# Generated by FakeRAM 2.0
VERSION 5.7 ;
BUSBITCHARS "[]" ;
PROPERTYDEFINITIONS
  MACRO width INTEGER ;
  MACRO depth INTEGER ;
  MACRO banks INTEGER ;
END PROPERTYDEFINITIONS
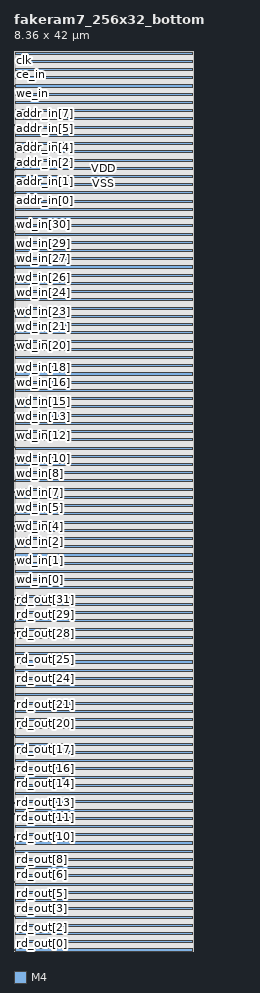
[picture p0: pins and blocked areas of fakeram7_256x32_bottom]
MACRO fakeram7_256x32_bottom
  PROPERTY width 32 ;
  PROPERTY depth 256 ;
  PROPERTY banks 2 ;
  FOREIGN fakeram7_256x32_bottom 0 0 ;
  SYMMETRY X Y R90 ;
  SIZE 8.360 BY 42.000 ;
  CLASS BLOCK ;
  PIN rd_out[0]
    DIRECTION OUTPUT ;
    USE SIGNAL ;
    SHAPE ABUTMENT ;
    PORT
      LAYER M4 ;
      RECT 0.000 0.039 0.024 0.063 ;
    END
  END rd_out[0]
  PIN rd_out[1]
    DIRECTION OUTPUT ;
    USE SIGNAL ;
    SHAPE ABUTMENT ;
    PORT
      LAYER M4 ;
      RECT 0.000 0.567 0.024 0.591 ;
    END
  END rd_out[1]
  PIN rd_out[2]
    DIRECTION OUTPUT ;
    USE SIGNAL ;
    SHAPE ABUTMENT ;
    PORT
      LAYER M4 ;
      RECT 0.000 1.095 0.024 1.119 ;
    END
  END rd_out[2]
  PIN rd_out[3]
    DIRECTION OUTPUT ;
    USE SIGNAL ;
    SHAPE ABUTMENT ;
    PORT
      LAYER M4 ;
      RECT 0.000 1.623 0.024 1.647 ;
    END
  END rd_out[3]
  PIN rd_out[4]
    DIRECTION OUTPUT ;
    USE SIGNAL ;
    SHAPE ABUTMENT ;
    PORT
      LAYER M4 ;
      RECT 0.000 2.151 0.024 2.175 ;
    END
  END rd_out[4]
  PIN rd_out[5]
    DIRECTION OUTPUT ;
    USE SIGNAL ;
    SHAPE ABUTMENT ;
    PORT
      LAYER M4 ;
      RECT 0.000 2.679 0.024 2.703 ;
    END
  END rd_out[5]
  PIN rd_out[6]
    DIRECTION OUTPUT ;
    USE SIGNAL ;
    SHAPE ABUTMENT ;
    PORT
      LAYER M4 ;
      RECT 0.000 3.207 0.024 3.231 ;
    END
  END rd_out[6]
  PIN rd_out[7]
    DIRECTION OUTPUT ;
    USE SIGNAL ;
    SHAPE ABUTMENT ;
    PORT
      LAYER M4 ;
      RECT 0.000 3.735 0.024 3.759 ;
    END
  END rd_out[7]
  PIN rd_out[8]
    DIRECTION OUTPUT ;
    USE SIGNAL ;
    SHAPE ABUTMENT ;
    PORT
      LAYER M4 ;
      RECT 0.000 4.263 0.024 4.287 ;
    END
  END rd_out[8]
  PIN rd_out[9]
    DIRECTION OUTPUT ;
    USE SIGNAL ;
    SHAPE ABUTMENT ;
    PORT
      LAYER M4 ;
      RECT 0.000 4.791 0.024 4.815 ;
    END
  END rd_out[9]
  PIN rd_out[10]
    DIRECTION OUTPUT ;
    USE SIGNAL ;
    SHAPE ABUTMENT ;
    PORT
      LAYER M4 ;
      RECT 0.000 5.319 0.024 5.343 ;
    END
  END rd_out[10]
  PIN rd_out[11]
    DIRECTION OUTPUT ;
    USE SIGNAL ;
    SHAPE ABUTMENT ;
    PORT
      LAYER M4 ;
      RECT 0.000 5.847 0.024 5.871 ;
    END
  END rd_out[11]
  PIN rd_out[12]
    DIRECTION OUTPUT ;
    USE SIGNAL ;
    SHAPE ABUTMENT ;
    PORT
      LAYER M4 ;
      RECT 0.000 6.375 0.024 6.399 ;
    END
  END rd_out[12]
  PIN rd_out[13]
    DIRECTION OUTPUT ;
    USE SIGNAL ;
    SHAPE ABUTMENT ;
    PORT
      LAYER M4 ;
      RECT 0.000 6.903 0.024 6.927 ;
    END
  END rd_out[13]
  PIN rd_out[14]
    DIRECTION OUTPUT ;
    USE SIGNAL ;
    SHAPE ABUTMENT ;
    PORT
      LAYER M4 ;
      RECT 0.000 7.431 0.024 7.455 ;
    END
  END rd_out[14]
  PIN rd_out[15]
    DIRECTION OUTPUT ;
    USE SIGNAL ;
    SHAPE ABUTMENT ;
    PORT
      LAYER M4 ;
      RECT 0.000 7.959 0.024 7.983 ;
    END
  END rd_out[15]
  PIN rd_out[16]
    DIRECTION OUTPUT ;
    USE SIGNAL ;
    SHAPE ABUTMENT ;
    PORT
      LAYER M4 ;
      RECT 0.000 8.487 0.024 8.511 ;
    END
  END rd_out[16]
  PIN rd_out[17]
    DIRECTION OUTPUT ;
    USE SIGNAL ;
    SHAPE ABUTMENT ;
    PORT
      LAYER M4 ;
      RECT 0.000 9.015 0.024 9.039 ;
    END
  END rd_out[17]
  PIN rd_out[18]
    DIRECTION OUTPUT ;
    USE SIGNAL ;
    SHAPE ABUTMENT ;
    PORT
      LAYER M4 ;
      RECT 0.000 9.543 0.024 9.567 ;
    END
  END rd_out[18]
  PIN rd_out[19]
    DIRECTION OUTPUT ;
    USE SIGNAL ;
    SHAPE ABUTMENT ;
    PORT
      LAYER M4 ;
      RECT 0.000 10.071 0.024 10.095 ;
    END
  END rd_out[19]
  PIN rd_out[20]
    DIRECTION OUTPUT ;
    USE SIGNAL ;
    SHAPE ABUTMENT ;
    PORT
      LAYER M4 ;
      RECT 0.000 10.599 0.024 10.623 ;
    END
  END rd_out[20]
  PIN rd_out[21]
    DIRECTION OUTPUT ;
    USE SIGNAL ;
    SHAPE ABUTMENT ;
    PORT
      LAYER M4 ;
      RECT 0.000 11.127 0.024 11.151 ;
    END
  END rd_out[21]
  PIN rd_out[22]
    DIRECTION OUTPUT ;
    USE SIGNAL ;
    SHAPE ABUTMENT ;
    PORT
      LAYER M4 ;
      RECT 0.000 11.655 0.024 11.679 ;
    END
  END rd_out[22]
  PIN rd_out[23]
    DIRECTION OUTPUT ;
    USE SIGNAL ;
    SHAPE ABUTMENT ;
    PORT
      LAYER M4 ;
      RECT 0.000 12.183 0.024 12.207 ;
    END
  END rd_out[23]
  PIN rd_out[24]
    DIRECTION OUTPUT ;
    USE SIGNAL ;
    SHAPE ABUTMENT ;
    PORT
      LAYER M4 ;
      RECT 0.000 12.711 0.024 12.735 ;
    END
  END rd_out[24]
  PIN rd_out[25]
    DIRECTION OUTPUT ;
    USE SIGNAL ;
    SHAPE ABUTMENT ;
    PORT
      LAYER M4 ;
      RECT 0.000 13.239 0.024 13.263 ;
    END
  END rd_out[25]
  PIN rd_out[26]
    DIRECTION OUTPUT ;
    USE SIGNAL ;
    SHAPE ABUTMENT ;
    PORT
      LAYER M4 ;
      RECT 0.000 13.767 0.024 13.791 ;
    END
  END rd_out[26]
  PIN rd_out[27]
    DIRECTION OUTPUT ;
    USE SIGNAL ;
    SHAPE ABUTMENT ;
    PORT
      LAYER M4 ;
      RECT 0.000 14.295 0.024 14.319 ;
    END
  END rd_out[27]
  PIN rd_out[28]
    DIRECTION OUTPUT ;
    USE SIGNAL ;
    SHAPE ABUTMENT ;
    PORT
      LAYER M4 ;
      RECT 0.000 14.823 0.024 14.847 ;
    END
  END rd_out[28]
  PIN rd_out[29]
    DIRECTION OUTPUT ;
    USE SIGNAL ;
    SHAPE ABUTMENT ;
    PORT
      LAYER M4 ;
      RECT 0.000 15.351 0.024 15.375 ;
    END
  END rd_out[29]
  PIN rd_out[30]
    DIRECTION OUTPUT ;
    USE SIGNAL ;
    SHAPE ABUTMENT ;
    PORT
      LAYER M4 ;
      RECT 0.000 15.879 0.024 15.903 ;
    END
  END rd_out[30]
  PIN rd_out[31]
    DIRECTION OUTPUT ;
    USE SIGNAL ;
    SHAPE ABUTMENT ;
    PORT
      LAYER M4 ;
      RECT 0.000 16.407 0.024 16.431 ;
    END
  END rd_out[31]
  PIN wd_in[0]
    DIRECTION INPUT ;
    USE SIGNAL ;
    SHAPE ABUTMENT ;
    PORT
      LAYER M4 ;
      RECT 0.000 17.703 0.024 17.727 ;
    END
  END wd_in[0]
  PIN wd_in[1]
    DIRECTION INPUT ;
    USE SIGNAL ;
    SHAPE ABUTMENT ;
    PORT
      LAYER M4 ;
      RECT 0.000 18.231 0.024 18.255 ;
    END
  END wd_in[1]
  PIN wd_in[2]
    DIRECTION INPUT ;
    USE SIGNAL ;
    SHAPE ABUTMENT ;
    PORT
      LAYER M4 ;
      RECT 0.000 18.759 0.024 18.783 ;
    END
  END wd_in[2]
  PIN wd_in[3]
    DIRECTION INPUT ;
    USE SIGNAL ;
    SHAPE ABUTMENT ;
    PORT
      LAYER M4 ;
      RECT 0.000 19.287 0.024 19.311 ;
    END
  END wd_in[3]
  PIN wd_in[4]
    DIRECTION INPUT ;
    USE SIGNAL ;
    SHAPE ABUTMENT ;
    PORT
      LAYER M4 ;
      RECT 0.000 19.815 0.024 19.839 ;
    END
  END wd_in[4]
  PIN wd_in[5]
    DIRECTION INPUT ;
    USE SIGNAL ;
    SHAPE ABUTMENT ;
    PORT
      LAYER M4 ;
      RECT 0.000 20.343 0.024 20.367 ;
    END
  END wd_in[5]
  PIN wd_in[6]
    DIRECTION INPUT ;
    USE SIGNAL ;
    SHAPE ABUTMENT ;
    PORT
      LAYER M4 ;
      RECT 0.000 20.871 0.024 20.895 ;
    END
  END wd_in[6]
  PIN wd_in[7]
    DIRECTION INPUT ;
    USE SIGNAL ;
    SHAPE ABUTMENT ;
    PORT
      LAYER M4 ;
      RECT 0.000 21.399 0.024 21.423 ;
    END
  END wd_in[7]
  PIN wd_in[8]
    DIRECTION INPUT ;
    USE SIGNAL ;
    SHAPE ABUTMENT ;
    PORT
      LAYER M4 ;
      RECT 0.000 21.927 0.024 21.951 ;
    END
  END wd_in[8]
  PIN wd_in[9]
    DIRECTION INPUT ;
    USE SIGNAL ;
    SHAPE ABUTMENT ;
    PORT
      LAYER M4 ;
      RECT 0.000 22.455 0.024 22.479 ;
    END
  END wd_in[9]
  PIN wd_in[10]
    DIRECTION INPUT ;
    USE SIGNAL ;
    SHAPE ABUTMENT ;
    PORT
      LAYER M4 ;
      RECT 0.000 22.983 0.024 23.007 ;
    END
  END wd_in[10]
  PIN wd_in[11]
    DIRECTION INPUT ;
    USE SIGNAL ;
    SHAPE ABUTMENT ;
    PORT
      LAYER M4 ;
      RECT 0.000 23.511 0.024 23.535 ;
    END
  END wd_in[11]
  PIN wd_in[12]
    DIRECTION INPUT ;
    USE SIGNAL ;
    SHAPE ABUTMENT ;
    PORT
      LAYER M4 ;
      RECT 0.000 24.039 0.024 24.063 ;
    END
  END wd_in[12]
  PIN wd_in[13]
    DIRECTION INPUT ;
    USE SIGNAL ;
    SHAPE ABUTMENT ;
    PORT
      LAYER M4 ;
      RECT 0.000 24.567 0.024 24.591 ;
    END
  END wd_in[13]
  PIN wd_in[14]
    DIRECTION INPUT ;
    USE SIGNAL ;
    SHAPE ABUTMENT ;
    PORT
      LAYER M4 ;
      RECT 0.000 25.095 0.024 25.119 ;
    END
  END wd_in[14]
  PIN wd_in[15]
    DIRECTION INPUT ;
    USE SIGNAL ;
    SHAPE ABUTMENT ;
    PORT
      LAYER M4 ;
      RECT 0.000 25.623 0.024 25.647 ;
    END
  END wd_in[15]
  PIN wd_in[16]
    DIRECTION INPUT ;
    USE SIGNAL ;
    SHAPE ABUTMENT ;
    PORT
      LAYER M4 ;
      RECT 0.000 26.151 0.024 26.175 ;
    END
  END wd_in[16]
  PIN wd_in[17]
    DIRECTION INPUT ;
    USE SIGNAL ;
    SHAPE ABUTMENT ;
    PORT
      LAYER M4 ;
      RECT 0.000 26.679 0.024 26.703 ;
    END
  END wd_in[17]
  PIN wd_in[18]
    DIRECTION INPUT ;
    USE SIGNAL ;
    SHAPE ABUTMENT ;
    PORT
      LAYER M4 ;
      RECT 0.000 27.207 0.024 27.231 ;
    END
  END wd_in[18]
  PIN wd_in[19]
    DIRECTION INPUT ;
    USE SIGNAL ;
    SHAPE ABUTMENT ;
    PORT
      LAYER M4 ;
      RECT 0.000 27.735 0.024 27.759 ;
    END
  END wd_in[19]
  PIN wd_in[20]
    DIRECTION INPUT ;
    USE SIGNAL ;
    SHAPE ABUTMENT ;
    PORT
      LAYER M4 ;
      RECT 0.000 28.263 0.024 28.287 ;
    END
  END wd_in[20]
  PIN wd_in[21]
    DIRECTION INPUT ;
    USE SIGNAL ;
    SHAPE ABUTMENT ;
    PORT
      LAYER M4 ;
      RECT 0.000 28.791 0.024 28.815 ;
    END
  END wd_in[21]
  PIN wd_in[22]
    DIRECTION INPUT ;
    USE SIGNAL ;
    SHAPE ABUTMENT ;
    PORT
      LAYER M4 ;
      RECT 0.000 29.319 0.024 29.343 ;
    END
  END wd_in[22]
  PIN wd_in[23]
    DIRECTION INPUT ;
    USE SIGNAL ;
    SHAPE ABUTMENT ;
    PORT
      LAYER M4 ;
      RECT 0.000 29.847 0.024 29.871 ;
    END
  END wd_in[23]
  PIN wd_in[24]
    DIRECTION INPUT ;
    USE SIGNAL ;
    SHAPE ABUTMENT ;
    PORT
      LAYER M4 ;
      RECT 0.000 30.375 0.024 30.399 ;
    END
  END wd_in[24]
  PIN wd_in[25]
    DIRECTION INPUT ;
    USE SIGNAL ;
    SHAPE ABUTMENT ;
    PORT
      LAYER M4 ;
      RECT 0.000 30.903 0.024 30.927 ;
    END
  END wd_in[25]
  PIN wd_in[26]
    DIRECTION INPUT ;
    USE SIGNAL ;
    SHAPE ABUTMENT ;
    PORT
      LAYER M4 ;
      RECT 0.000 31.431 0.024 31.455 ;
    END
  END wd_in[26]
  PIN wd_in[27]
    DIRECTION INPUT ;
    USE SIGNAL ;
    SHAPE ABUTMENT ;
    PORT
      LAYER M4 ;
      RECT 0.000 31.959 0.024 31.983 ;
    END
  END wd_in[27]
  PIN wd_in[28]
    DIRECTION INPUT ;
    USE SIGNAL ;
    SHAPE ABUTMENT ;
    PORT
      LAYER M4 ;
      RECT 0.000 32.487 0.024 32.511 ;
    END
  END wd_in[28]
  PIN wd_in[29]
    DIRECTION INPUT ;
    USE SIGNAL ;
    SHAPE ABUTMENT ;
    PORT
      LAYER M4 ;
      RECT 0.000 33.015 0.024 33.039 ;
    END
  END wd_in[29]
  PIN wd_in[30]
    DIRECTION INPUT ;
    USE SIGNAL ;
    SHAPE ABUTMENT ;
    PORT
      LAYER M4 ;
      RECT 0.000 33.543 0.024 33.567 ;
    END
  END wd_in[30]
  PIN wd_in[31]
    DIRECTION INPUT ;
    USE SIGNAL ;
    SHAPE ABUTMENT ;
    PORT
      LAYER M4 ;
      RECT 0.000 34.071 0.024 34.095 ;
    END
  END wd_in[31]
  PIN addr_in[0]
    DIRECTION INPUT ;
    USE SIGNAL ;
    SHAPE ABUTMENT ;
    PORT
      LAYER M4 ;
      RECT 0.000 35.367 0.024 35.391 ;
    END
  END addr_in[0]
  PIN addr_in[1]
    DIRECTION INPUT ;
    USE SIGNAL ;
    SHAPE ABUTMENT ;
    PORT
      LAYER M4 ;
      RECT 0.000 35.895 0.024 35.919 ;
    END
  END addr_in[1]
  PIN addr_in[2]
    DIRECTION INPUT ;
    USE SIGNAL ;
    SHAPE ABUTMENT ;
    PORT
      LAYER M4 ;
      RECT 0.000 36.423 0.024 36.447 ;
    END
  END addr_in[2]
  PIN addr_in[3]
    DIRECTION INPUT ;
    USE SIGNAL ;
    SHAPE ABUTMENT ;
    PORT
      LAYER M4 ;
      RECT 0.000 36.951 0.024 36.975 ;
    END
  END addr_in[3]
  PIN addr_in[4]
    DIRECTION INPUT ;
    USE SIGNAL ;
    SHAPE ABUTMENT ;
    PORT
      LAYER M4 ;
      RECT 0.000 37.479 0.024 37.503 ;
    END
  END addr_in[4]
  PIN addr_in[5]
    DIRECTION INPUT ;
    USE SIGNAL ;
    SHAPE ABUTMENT ;
    PORT
      LAYER M4 ;
      RECT 0.000 38.007 0.024 38.031 ;
    END
  END addr_in[5]
  PIN addr_in[6]
    DIRECTION INPUT ;
    USE SIGNAL ;
    SHAPE ABUTMENT ;
    PORT
      LAYER M4 ;
      RECT 0.000 38.535 0.024 38.559 ;
    END
  END addr_in[6]
  PIN addr_in[7]
    DIRECTION INPUT ;
    USE SIGNAL ;
    SHAPE ABUTMENT ;
    PORT
      LAYER M4 ;
      RECT 0.000 39.063 0.024 39.087 ;
    END
  END addr_in[7]
  PIN we_in
    DIRECTION INPUT ;
    USE SIGNAL ;
    SHAPE ABUTMENT ;
    PORT
      LAYER M4 ;
      RECT 0.000 40.359 0.024 40.383 ;
    END
  END we_in
  PIN ce_in
    DIRECTION INPUT ;
    USE SIGNAL ;
    SHAPE ABUTMENT ;
    PORT
      LAYER M4 ;
      RECT 0.000 40.887 0.024 40.911 ;
    END
  END ce_in
  PIN clk
    DIRECTION INPUT ;
    USE SIGNAL ;
    SHAPE ABUTMENT ;
    PORT
      LAYER M4 ;
      RECT 0.000 41.415 0.024 41.439 ;
    END
  END clk
  PIN VSS
    DIRECTION INOUT ;
    USE GROUND ;
    PORT
      LAYER M4 ;
      RECT 0.048 0.000 8.312 0.096 ;
      RECT 0.048 0.768 8.312 0.864 ;
      RECT 0.048 1.536 8.312 1.632 ;
      RECT 0.048 2.304 8.312 2.400 ;
      RECT 0.048 3.072 8.312 3.168 ;
      RECT 0.048 3.840 8.312 3.936 ;
      RECT 0.048 4.608 8.312 4.704 ;
      RECT 0.048 5.376 8.312 5.472 ;
      RECT 0.048 6.144 8.312 6.240 ;
      RECT 0.048 6.912 8.312 7.008 ;
      RECT 0.048 7.680 8.312 7.776 ;
      RECT 0.048 8.448 8.312 8.544 ;
      RECT 0.048 9.216 8.312 9.312 ;
      RECT 0.048 9.984 8.312 10.080 ;
      RECT 0.048 10.752 8.312 10.848 ;
      RECT 0.048 11.520 8.312 11.616 ;
      RECT 0.048 12.288 8.312 12.384 ;
      RECT 0.048 13.056 8.312 13.152 ;
      RECT 0.048 13.824 8.312 13.920 ;
      RECT 0.048 14.592 8.312 14.688 ;
      RECT 0.048 15.360 8.312 15.456 ;
      RECT 0.048 16.128 8.312 16.224 ;
      RECT 0.048 16.896 8.312 16.992 ;
      RECT 0.048 17.664 8.312 17.760 ;
      RECT 0.048 18.432 8.312 18.528 ;
      RECT 0.048 19.200 8.312 19.296 ;
      RECT 0.048 19.968 8.312 20.064 ;
      RECT 0.048 20.736 8.312 20.832 ;
      RECT 0.048 21.504 8.312 21.600 ;
      RECT 0.048 22.272 8.312 22.368 ;
      RECT 0.048 23.040 8.312 23.136 ;
      RECT 0.048 23.808 8.312 23.904 ;
      RECT 0.048 24.576 8.312 24.672 ;
      RECT 0.048 25.344 8.312 25.440 ;
      RECT 0.048 26.112 8.312 26.208 ;
      RECT 0.048 26.880 8.312 26.976 ;
      RECT 0.048 27.648 8.312 27.744 ;
      RECT 0.048 28.416 8.312 28.512 ;
      RECT 0.048 29.184 8.312 29.280 ;
      RECT 0.048 29.952 8.312 30.048 ;
      RECT 0.048 30.720 8.312 30.816 ;
      RECT 0.048 31.488 8.312 31.584 ;
      RECT 0.048 32.256 8.312 32.352 ;
      RECT 0.048 33.024 8.312 33.120 ;
      RECT 0.048 33.792 8.312 33.888 ;
      RECT 0.048 34.560 8.312 34.656 ;
      RECT 0.048 35.328 8.312 35.424 ;
      RECT 0.048 36.096 8.312 36.192 ;
      RECT 0.048 36.864 8.312 36.960 ;
      RECT 0.048 37.632 8.312 37.728 ;
      RECT 0.048 38.400 8.312 38.496 ;
      RECT 0.048 39.168 8.312 39.264 ;
      RECT 0.048 39.936 8.312 40.032 ;
      RECT 0.048 40.704 8.312 40.800 ;
      RECT 0.048 41.472 8.312 41.568 ;
    END
  END VSS
  PIN VDD
    DIRECTION INOUT ;
    USE POWER ;
    PORT
      LAYER M4 ;
      RECT 0.048 0.384 8.312 0.480 ;
      RECT 0.048 1.152 8.312 1.248 ;
      RECT 0.048 1.920 8.312 2.016 ;
      RECT 0.048 2.688 8.312 2.784 ;
      RECT 0.048 3.456 8.312 3.552 ;
      RECT 0.048 4.224 8.312 4.320 ;
      RECT 0.048 4.992 8.312 5.088 ;
      RECT 0.048 5.760 8.312 5.856 ;
      RECT 0.048 6.528 8.312 6.624 ;
      RECT 0.048 7.296 8.312 7.392 ;
      RECT 0.048 8.064 8.312 8.160 ;
      RECT 0.048 8.832 8.312 8.928 ;
      RECT 0.048 9.600 8.312 9.696 ;
      RECT 0.048 10.368 8.312 10.464 ;
      RECT 0.048 11.136 8.312 11.232 ;
      RECT 0.048 11.904 8.312 12.000 ;
      RECT 0.048 12.672 8.312 12.768 ;
      RECT 0.048 13.440 8.312 13.536 ;
      RECT 0.048 14.208 8.312 14.304 ;
      RECT 0.048 14.976 8.312 15.072 ;
      RECT 0.048 15.744 8.312 15.840 ;
      RECT 0.048 16.512 8.312 16.608 ;
      RECT 0.048 17.280 8.312 17.376 ;
      RECT 0.048 18.048 8.312 18.144 ;
      RECT 0.048 18.816 8.312 18.912 ;
      RECT 0.048 19.584 8.312 19.680 ;
      RECT 0.048 20.352 8.312 20.448 ;
      RECT 0.048 21.120 8.312 21.216 ;
      RECT 0.048 21.888 8.312 21.984 ;
      RECT 0.048 22.656 8.312 22.752 ;
      RECT 0.048 23.424 8.312 23.520 ;
      RECT 0.048 24.192 8.312 24.288 ;
      RECT 0.048 24.960 8.312 25.056 ;
      RECT 0.048 25.728 8.312 25.824 ;
      RECT 0.048 26.496 8.312 26.592 ;
      RECT 0.048 27.264 8.312 27.360 ;
      RECT 0.048 28.032 8.312 28.128 ;
      RECT 0.048 28.800 8.312 28.896 ;
      RECT 0.048 29.568 8.312 29.664 ;
      RECT 0.048 30.336 8.312 30.432 ;
      RECT 0.048 31.104 8.312 31.200 ;
      RECT 0.048 31.872 8.312 31.968 ;
      RECT 0.048 32.640 8.312 32.736 ;
      RECT 0.048 33.408 8.312 33.504 ;
      RECT 0.048 34.176 8.312 34.272 ;
      RECT 0.048 34.944 8.312 35.040 ;
      RECT 0.048 35.712 8.312 35.808 ;
      RECT 0.048 36.480 8.312 36.576 ;
      RECT 0.048 37.248 8.312 37.344 ;
      RECT 0.048 38.016 8.312 38.112 ;
      RECT 0.048 38.784 8.312 38.880 ;
      RECT 0.048 39.552 8.312 39.648 ;
      RECT 0.048 40.320 8.312 40.416 ;
      RECT 0.048 41.088 8.312 41.184 ;
      RECT 0.048 41.856 8.312 41.952 ;
    END
  END VDD
  OBS
    LAYER M1 ;
    RECT 0 0 8.360 42.000 ;
    LAYER M2 ;
    RECT 0 0 8.360 42.000 ;
    LAYER M3 ;
    RECT 0.059 0.000 8.360 42.000 ;
    LAYER M4 ;
    RECT 0.059 0.000 8.360 42.000 ;
  END
END fakeram7_256x32_bottom

END LIBRARY
